VERSION 5.8 ;
BUSBITCHARS "[]" ;
DIVIDERCHAR "/" ;
UNITS
    DATABASE MICRONS 1000 ;
END UNITS

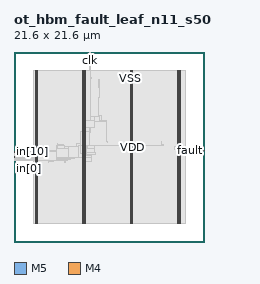
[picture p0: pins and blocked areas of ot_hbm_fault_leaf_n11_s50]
MACRO ot_hbm_fault_leaf_n11_s50
  FOREIGN ot_hbm_fault_leaf_n11_s50 0 0 ;
  CLASS BLOCK ;
  SIZE 21.6 BY 21.6 ;
  PIN clk
    DIRECTION INPUT ;
    USE SIGNAL ;
    PORT
      LAYER M5 ;
        RECT  8.592 21.516 8.616 21.6 ;
    END
  END clk
  PIN fault
    DIRECTION OUTPUT ;
    USE SIGNAL ;
    PORT
      LAYER M4 ;
        RECT  21.516 10.416 21.6 10.44 ;
    END
    PORT
      LAYER M4 ;
        RECT  20.293 10.416 21.564 10.44 ;
    END
  END fault
  PIN in[0]
    DIRECTION INPUT ;
    USE SIGNAL ;
    PORT
      LAYER M4 ;
        RECT  0 9.264 0.084 9.288 ;
    END
  END in[0]
  PIN in[10]
    DIRECTION INPUT ;
    USE SIGNAL ;
    PORT
      LAYER M4 ;
        RECT  0 10.224 0.084 10.248 ;
    END
  END in[10]
  PIN in[1]
    DIRECTION INPUT ;
    USE SIGNAL ;
    PORT
      LAYER M4 ;
        RECT  0 9.36 0.084 9.384 ;
    END
  END in[1]
  PIN in[2]
    DIRECTION INPUT ;
    USE SIGNAL ;
    PORT
      LAYER M4 ;
        RECT  0 9.456 0.084 9.48 ;
    END
  END in[2]
  PIN in[3]
    DIRECTION INPUT ;
    USE SIGNAL ;
    PORT
      LAYER M4 ;
        RECT  0 9.552 0.084 9.576 ;
    END
  END in[3]
  PIN in[4]
    DIRECTION INPUT ;
    USE SIGNAL ;
    PORT
      LAYER M4 ;
        RECT  0 9.648 0.084 9.672 ;
    END
  END in[4]
  PIN in[5]
    DIRECTION INPUT ;
    USE SIGNAL ;
    PORT
      LAYER M4 ;
        RECT  0 9.744 0.084 9.768 ;
    END
  END in[5]
  PIN in[6]
    DIRECTION INPUT ;
    USE SIGNAL ;
    PORT
      LAYER M4 ;
        RECT  0 9.84 0.084 9.864 ;
    END
  END in[6]
  PIN in[7]
    DIRECTION INPUT ;
    USE SIGNAL ;
    PORT
      LAYER M4 ;
        RECT  0 9.936 0.084 9.96 ;
    END
  END in[7]
  PIN in[8]
    DIRECTION INPUT ;
    USE SIGNAL ;
    PORT
      LAYER M4 ;
        RECT  0 10.032 0.084 10.056 ;
    END
  END in[8]
  PIN in[9]
    DIRECTION INPUT ;
    USE SIGNAL ;
    PORT
      LAYER M4 ;
        RECT  0 10.128 0.084 10.152 ;
    END
  END in[9]
  PIN rst_n
    DIRECTION INPUT ;
    USE SIGNAL ;
    PORT
      LAYER M5 ;
        RECT  8.688 21.516 8.712 21.6 ;
    END
  END rst_n
  PIN VDD
    DIRECTION INOUT ;
    USE POWER ;
    PORT
      LAYER M5 ;
        RECT  18.792 2.151 18.912 19.449 ;
        RECT  13.392 2.151 13.512 19.449 ;
        RECT  7.992 2.151 8.112 19.449 ;
        RECT  2.592 2.151 2.712 19.449 ;
    END
  END VDD
  PIN VSS
    DIRECTION INOUT ;
    USE GROUND ;
    PORT
      LAYER M5 ;
        RECT  18.6 2.137 18.72 19.463 ;
        RECT  13.2 2.137 13.32 19.463 ;
        RECT  7.8 2.137 7.92 19.463 ;
        RECT  2.4 2.137 2.52 19.463 ;
    END
  END VSS
  # OT_OBS_CLOSED layer=M5 d_um=1.536 added=0
  OBS
    LAYER RVTN ;
     RECT  2.16 2.16 19.44 2.295 ;
     RECT  2.16 2.565 19.44 2.835 ;
     RECT  2.16 3.105 19.44 3.375 ;
     RECT  2.16 3.645 19.44 3.915 ;
     RECT  2.16 4.185 19.44 4.455 ;
     RECT  2.16 4.725 19.44 4.995 ;
     RECT  2.16 5.265 19.44 5.535 ;
     RECT  2.16 5.805 19.44 6.075 ;
     RECT  2.16 6.345 19.44 6.615 ;
     RECT  2.16 6.885 19.44 7.155 ;
     RECT  2.16 7.425 19.44 7.695 ;
     RECT  2.16 7.965 19.44 8.235 ;
     RECT  2.16 8.505 19.44 8.775 ;
     RECT  2.16 9.045 19.44 9.315 ;
     RECT  2.16 9.585 19.44 9.855 ;
     RECT  2.16 10.125 19.44 10.395 ;
     RECT  2.16 10.665 19.44 10.935 ;
     RECT  2.16 11.205 19.44 11.475 ;
     RECT  2.16 11.745 19.44 12.015 ;
     RECT  2.16 12.285 19.44 12.555 ;
     RECT  2.16 12.825 19.44 13.095 ;
     RECT  2.16 13.365 19.44 13.635 ;
     RECT  2.16 13.905 19.44 14.175 ;
     RECT  2.16 14.445 19.44 14.715 ;
     RECT  2.16 14.985 19.44 15.255 ;
     RECT  2.16 15.525 19.44 15.795 ;
     RECT  2.16 16.065 19.44 16.335 ;
     RECT  2.16 16.605 19.44 16.875 ;
     RECT  2.16 17.145 19.44 17.415 ;
     RECT  2.16 17.685 19.44 17.955 ;
     RECT  2.16 18.225 19.44 18.495 ;
     RECT  2.16 18.765 19.44 19.035 ;
     RECT  2.16 19.305 19.44 19.44 ;
    LAYER RVTP ;
     RECT  2.16 2.295 19.44 2.565 ;
     RECT  2.16 2.835 19.44 3.105 ;
     RECT  2.16 3.375 19.44 3.645 ;
     RECT  2.16 3.915 19.44 4.185 ;
     RECT  2.16 4.455 19.44 4.725 ;
     RECT  2.16 4.995 19.44 5.265 ;
     RECT  2.16 5.535 19.44 5.805 ;
     RECT  2.16 6.075 19.44 6.345 ;
     RECT  2.16 6.615 19.44 6.885 ;
     RECT  2.16 7.155 19.44 7.425 ;
     RECT  2.16 7.695 19.44 7.965 ;
     RECT  2.16 8.235 19.44 8.505 ;
     RECT  2.16 8.775 19.44 9.045 ;
     RECT  2.16 9.315 19.44 9.585 ;
     RECT  2.16 9.855 19.44 10.125 ;
     RECT  2.16 10.395 19.44 10.665 ;
     RECT  2.16 10.935 19.44 11.205 ;
     RECT  2.16 11.475 19.44 11.745 ;
     RECT  2.16 12.015 19.44 12.285 ;
     RECT  2.16 12.555 19.44 12.825 ;
     RECT  2.16 13.095 19.44 13.365 ;
     RECT  2.16 13.635 19.44 13.905 ;
     RECT  2.16 14.175 19.44 14.445 ;
     RECT  2.16 14.715 19.44 14.985 ;
     RECT  2.16 15.255 19.44 15.525 ;
     RECT  2.16 15.795 19.44 16.065 ;
     RECT  2.16 16.335 19.44 16.605 ;
     RECT  2.16 16.875 19.44 17.145 ;
     RECT  2.16 17.415 19.44 17.685 ;
     RECT  2.16 17.955 19.44 18.225 ;
     RECT  2.16 18.495 19.44 18.765 ;
     RECT  2.16 19.035 19.44 19.305 ;
    LAYER M1 ;
     RECT  2.16 2.151 19.44 19.449 ;
    LAYER M2 ;
     RECT  0.103 9.828 0.203 9.846 ;
     RECT  2.16 2.151 19.44 19.449 ;
     RECT  19.44 10.476 20.327 10.494 ;
    LAYER M3 ;
     RECT  2.415 2.143 2.505 2.413 ;
     RECT  7.815 2.143 7.905 2.413 ;
     RECT  13.215 2.143 13.305 2.413 ;
     RECT  18.615 2.143 18.705 2.413 ;
     RECT  3.96 9.085 3.978 9.121 ;
     RECT  7.815 2.413 8.097 9.121 ;
     RECT  3.96 9.121 4.446 9.211 ;
     RECT  5.688 9.085 5.886 9.211 ;
     RECT  2.415 2.413 2.697 9.307 ;
     RECT  3.96 9.211 5.886 9.319 ;
     RECT  2.415 9.307 2.718 9.355 ;
     RECT  3.96 9.319 6.066 9.383 ;
     RECT  4.068 9.383 6.066 9.391 ;
     RECT  4.068 9.391 6.39 9.547 ;
     RECT  7.815 9.121 8.802 9.625 ;
     RECT  4.068 9.547 6.858 9.689 ;
     RECT  0.18 9.595 0.198 9.82 ;
     RECT  5.688 9.689 6.858 9.883 ;
     RECT  7.815 9.625 8.838 9.883 ;
     RECT  0.108 9.82 0.198 9.917 ;
     RECT  5.688 9.883 8.838 9.931 ;
     RECT  0.108 9.917 0.126 9.965 ;
     RECT  5.688 9.931 9.306 10.121 ;
     RECT  2.304 9.355 3.222 10.253 ;
     RECT  2.304 10.253 2.862 10.355 ;
     RECT  4.068 9.689 4.878 10.355 ;
     RECT  18.615 2.413 18.897 10.471 ;
     RECT  20.304 10.411 20.322 10.499 ;
     RECT  5.688 10.121 9.162 10.625 ;
     RECT  5.688 10.625 8.334 10.685 ;
     RECT  9.108 10.625 9.162 10.697 ;
     RECT  4.788 10.355 4.878 10.705 ;
     RECT  2.415 10.355 2.862 10.769 ;
     RECT  5.688 10.685 6.246 10.859 ;
     RECT  18.216 10.471 18.897 10.859 ;
     RECT  5.688 10.859 6.21 10.877 ;
     RECT  5.688 10.877 5.742 10.967 ;
     RECT  4.788 10.705 4.95 10.975 ;
     RECT  16.164 10.939 16.758 10.975 ;
     RECT  16.164 10.975 16.974 10.976 ;
     RECT  4.788 10.975 5.598 11.003 ;
     RECT  9.108 10.697 9.126 11.003 ;
     RECT  4.932 11.003 5.598 11.129 ;
     RECT  16.74 10.976 16.974 11.129 ;
     RECT  4.932 11.129 4.95 11.165 ;
     RECT  7.056 10.685 8.334 11.165 ;
     RECT  7.815 11.165 8.334 11.309 ;
     RECT  10.584 11.281 10.602 11.371 ;
     RECT  10.512 11.371 10.602 11.399 ;
     RECT  16.74 11.129 16.758 11.399 ;
     RECT  7.815 11.309 8.097 12.427 ;
     RECT  10.512 11.399 10.53 12.749 ;
     RECT  7.815 12.427 8.622 13.091 ;
     RECT  10.548 12.865 10.566 13.675 ;
     RECT  9.828 13.675 10.566 13.819 ;
     RECT  9.576 13.819 10.566 13.829 ;
     RECT  9.576 13.829 9.918 14.369 ;
     RECT  9.576 14.369 9.594 16.411 ;
     RECT  9.576 16.411 9.774 16.439 ;
     RECT  9.756 16.439 9.774 17.609 ;
     RECT  7.815 13.091 8.097 18.235 ;
     RECT  9.648 17.617 9.666 18.419 ;
     RECT  7.815 18.235 8.694 18.571 ;
     RECT  7.815 18.571 8.838 18.689 ;
     RECT  7.815 18.689 8.694 18.845 ;
     RECT  2.415 10.769 2.697 19.187 ;
     RECT  7.815 18.845 8.097 19.187 ;
     RECT  13.215 2.413 13.497 19.187 ;
     RECT  18.615 10.859 18.897 19.187 ;
     RECT  2.415 19.187 2.505 19.457 ;
     RECT  7.815 19.187 7.905 19.457 ;
     RECT  13.215 19.187 13.305 19.457 ;
     RECT  18.615 19.187 18.705 19.457 ;
    LAYER M4 ;
     RECT  0.084 9.264 2.408 9.288 ;
     RECT  0.06 9.288 2.408 9.36 ;
     RECT  0.084 9.36 2.408 9.384 ;
     RECT  0.06 9.384 2.408 9.456 ;
     RECT  0.084 9.456 2.408 9.48 ;
     RECT  0.06 9.48 2.408 9.552 ;
     RECT  0.084 9.552 2.408 9.576 ;
     RECT  0.06 9.576 2.408 9.648 ;
     RECT  0.084 9.648 2.408 9.672 ;
     RECT  0.06 9.672 2.408 9.744 ;
     RECT  0.084 9.744 2.408 9.768 ;
     RECT  0.06 9.768 2.408 9.84 ;
     RECT  0.084 9.84 2.408 9.864 ;
     RECT  0.06 9.864 2.408 9.936 ;
     RECT  0.084 9.936 2.408 9.96 ;
     RECT  0.06 9.96 2.408 10.032 ;
     RECT  0.084 10.032 2.408 10.056 ;
     RECT  0.06 10.056 2.408 10.128 ;
     RECT  0.084 10.128 2.408 10.152 ;
     RECT  0.06 10.152 2.408 10.224 ;
     RECT  0.084 10.224 2.408 10.248 ;
     RECT  2.408 2.148 2.512 19.452 ;
     RECT  2.512 2.418 2.704 19.182 ;
     RECT  2.704 9.312 4.777 10.248 ;
     RECT  4.777 9.312 4.817 10.872 ;
     RECT  4.817 9.552 4.861 10.872 ;
     RECT  4.861 9.552 6.181 10.584 ;
     RECT  6.181 9.552 7.297 10.872 ;
     RECT  7.297 9.552 7.808 10.968 ;
     RECT  7.525 12.528 7.808 12.552 ;
     RECT  7.808 2.148 7.912 19.452 ;
     RECT  7.912 2.418 8.104 19.182 ;
     RECT  8.104 10.08 8.243 10.968 ;
     RECT  8.243 10.656 8.345 10.968 ;
     RECT  8.104 12.432 8.668 14.232 ;
     RECT  8.104 18.24 8.723 18.84 ;
     RECT  8.723 18.24 8.749 18.264 ;
     RECT  8.668 13.008 9.107 14.232 ;
     RECT  9.107 13.68 9.713 14.232 ;
     RECT  9.713 13.68 9.857 13.704 ;
     RECT  8.345 10.944 13.208 10.968 ;
     RECT  13.208 2.148 13.312 19.452 ;
     RECT  13.312 2.418 13.504 19.182 ;
     RECT  13.504 10.944 16.193 10.968 ;
     RECT  18.608 2.148 18.712 19.452 ;
     RECT  18.712 2.418 18.904 19.182 ;
    LAYER M5 ;
     RECT  2.4 2.137 2.52 2.151 ;
     RECT  7.8 2.137 7.92 2.151 ;
     RECT  13.2 2.137 13.32 2.151 ;
     RECT  18.6 2.137 18.72 2.151 ;
     RECT  0.192 9.589 0.216 9.827 ;
     RECT  7.8 2.151 8.112 10.069 ;
     RECT  4.8 10.069 4.824 10.883 ;
     RECT  7.536 10.069 8.232 10.933 ;
     RECT  7.536 10.933 8.616 12.563 ;
     RECT  7.8 12.563 8.616 12.997 ;
     RECT  7.8 12.997 9.096 13.859 ;
     RECT  2.4 2.151 2.712 19.449 ;
     RECT  13.2 2.151 13.512 19.449 ;
     RECT  18.6 2.151 18.912 19.449 ;
     RECT  2.4 19.449 2.52 19.463 ;
     RECT  7.8 13.859 8.712 19.463 ;
     RECT  13.2 19.449 13.32 19.463 ;
     RECT  18.6 19.449 18.72 19.463 ;
     RECT  8.592 19.463 8.712 21.516 ;
     RECT  8.616 21.516 8.688 21.584 ;
  END
END ot_hbm_fault_leaf_n11_s50
END LIBRARY
